One B-rep face of a CAD part: STEP entity #138.
In plain terms, the planar face has unit normal (1, 0, 0).
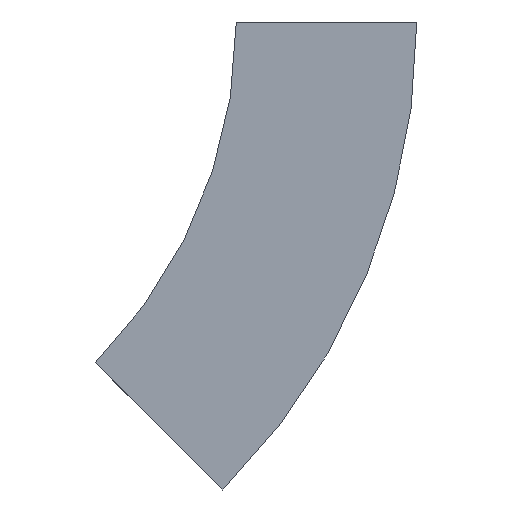
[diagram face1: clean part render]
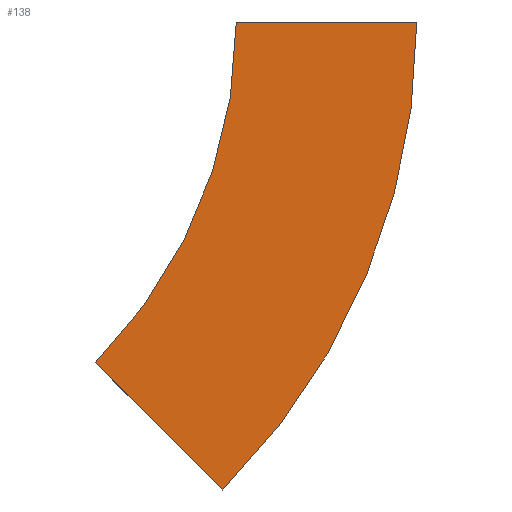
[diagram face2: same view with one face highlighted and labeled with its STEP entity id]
Its self-contained STEP definition (entity closure, numbers rounded to 3 decimals):
#17 = DIRECTION ( 'NONE',  ( 0., 1., 0. ) ) ;
#35 = CARTESIAN_POINT ( 'NONE',  ( 0., 300., 0. ) ) ;
#41 = ORIENTED_EDGE ( 'NONE', *, *, #254, .T. ) ;
#51 = VERTEX_POINT ( 'NONE', #505 ) ;
#66 = AXIS2_PLACEMENT_3D ( 'NONE', #35, #139, #316 ) ;
#67 = VECTOR ( 'NONE', #17, 1000. ) ;
#75 = EDGE_CURVE ( 'NONE', #51, #357, #349, .T. ) ;
#85 = AXIS2_PLACEMENT_3D ( 'NONE', #380, #302, #447 ) ;
#134 = AXIS2_PLACEMENT_3D ( 'NONE', #338, #554, #306 ) ;
#138 = ADVANCED_FACE ( 'NONE', ( #175 ), #383, .F. ) ;
#139 = DIRECTION ( 'NONE',  ( 1., 0., 0. ) ) ;
#149 = ORIENTED_EDGE ( 'NONE', *, *, #449, .F. ) ;
#169 = CARTESIAN_POINT ( 'NONE',  ( 0., 8.318, -291.682 ) ) ;
#175 = FACE_OUTER_BOUND ( 'NONE', #273, .T. ) ;
#208 = EDGE_CURVE ( 'NONE', #477, #357, #255, .T. ) ;
#218 = CARTESIAN_POINT ( 'NONE',  ( 0., 8.318, -291.682 ) ) ;
#254 = EDGE_CURVE ( 'NONE', #352, #477, #281, .T. ) ;
#255 = LINE ( 'NONE', #218, #548 ) ;
#273 = EDGE_LOOP ( 'NONE', ( #561, #149, #41, #521 ) ) ;
#281 = CIRCLE ( 'NONE', #85, 412.5 ) ;
#302 = DIRECTION ( 'NONE',  ( 1., 0., 0. ) ) ;
#306 = DIRECTION ( 'NONE',  ( 0., 0., 1. ) ) ;
#316 = DIRECTION ( 'NONE',  ( 0., -1., 0. ) ) ;
#338 = CARTESIAN_POINT ( 'NONE',  ( 0., -112.5, 0. ) ) ;
#342 = DIRECTION ( 'NONE',  ( 0., 0.707, 0.707 ) ) ;
#349 = CIRCLE ( 'NONE', #66, 300. ) ;
#352 = VERTEX_POINT ( 'NONE', #405 ) ;
#357 = VERTEX_POINT ( 'NONE', #443 ) ;
#380 = CARTESIAN_POINT ( 'NONE',  ( 0., 300., 0. ) ) ;
#383 = PLANE ( 'NONE',  #134 ) ;
#405 = CARTESIAN_POINT ( 'NONE',  ( 0., -112.5, 0. ) ) ;
#410 = LINE ( 'NONE', #493, #67 ) ;
#443 = CARTESIAN_POINT ( 'NONE',  ( 0., 87.868, -212.132 ) ) ;
#447 = DIRECTION ( 'NONE',  ( 0., -1., 0. ) ) ;
#449 = EDGE_CURVE ( 'NONE', #352, #51, #410, .T. ) ;
#477 = VERTEX_POINT ( 'NONE', #169 ) ;
#493 = CARTESIAN_POINT ( 'NONE',  ( 0., -112.5, 0. ) ) ;
#505 = CARTESIAN_POINT ( 'NONE',  ( 0., 0., 0. ) ) ;
#521 = ORIENTED_EDGE ( 'NONE', *, *, #208, .T. ) ;
#548 = VECTOR ( 'NONE', #342, 1000. ) ;
#554 = DIRECTION ( 'NONE',  ( -1., 0., 0. ) ) ;
#561 = ORIENTED_EDGE ( 'NONE', *, *, #75, .F. ) ;
